One B-rep face of a CAD part: STEP entity #77214.
In plain terms, the planar face has unit normal (0, 0, 1).
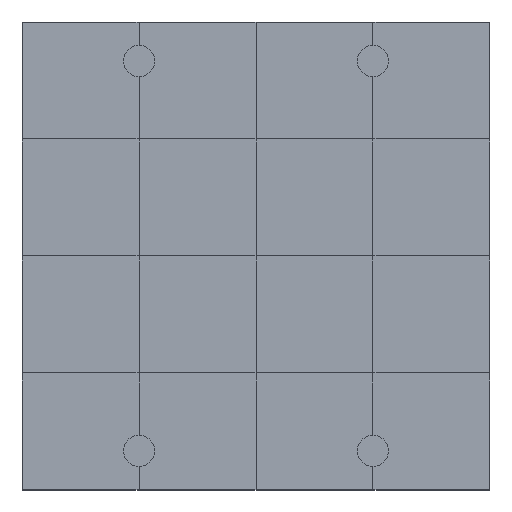
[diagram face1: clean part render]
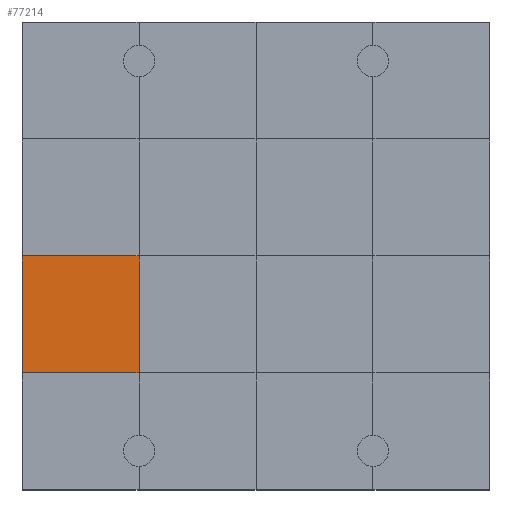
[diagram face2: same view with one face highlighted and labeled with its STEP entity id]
Its self-contained STEP definition (entity closure, numbers rounded to 3 decimals):
#76764 = VERTEX_POINT('',#76765);
#76765 = CARTESIAN_POINT('',(0.,3.,1.2));
#76779 = PLANE('',#76780);
#76780 = AXIS2_PLACEMENT_3D('',#76781,#76782,#76783);
#76781 = CARTESIAN_POINT('',(0.,3.,0.));
#76782 = DIRECTION('',(1.,0.,-0.));
#76783 = DIRECTION('',(0.,0.,1.));
#76805 = PLANE('',#76806);
#76806 = AXIS2_PLACEMENT_3D('',#76807,#76808,#76809);
#76807 = CARTESIAN_POINT('',(0.,0.,1.2));
#76808 = DIRECTION('',(0.,0.,1.));
#76809 = DIRECTION('',(1.,0.,-0.));
#76956 = VERTEX_POINT('',#76957);
#76957 = CARTESIAN_POINT('',(3.,3.,1.2));
#76978 = EDGE_CURVE('',#76764,#76956,#76979,.T.);
#76979 = SURFACE_CURVE('',#76980,(#76984,#76991),.PCURVE_S1.);
#76980 = LINE('',#76981,#76982);
#76981 = CARTESIAN_POINT('',(0.,3.,1.2));
#76982 = VECTOR('',#76983,1.);
#76983 = DIRECTION('',(1.,0.,-0.));
#76984 = PCURVE('',#76805,#76985);
#76985 = DEFINITIONAL_REPRESENTATION('',(#76986),#76990);
#76986 = LINE('',#76987,#76988);
#76987 = CARTESIAN_POINT('',(0.,3.));
#76988 = VECTOR('',#76989,1.);
#76989 = DIRECTION('',(1.,0.));
#76990 = ( GEOMETRIC_REPRESENTATION_CONTEXT(2) 
PARAMETRIC_REPRESENTATION_CONTEXT() REPRESENTATION_CONTEXT('2D SPACE',''
  ) );
#76991 = PCURVE('',#76992,#76997);
#76992 = PLANE('',#76993);
#76993 = AXIS2_PLACEMENT_3D('',#76994,#76995,#76996);
#76994 = CARTESIAN_POINT('',(0.,3.,1.2));
#76995 = DIRECTION('',(0.,0.,1.));
#76996 = DIRECTION('',(1.,0.,-0.));
#76997 = DEFINITIONAL_REPRESENTATION('',(#76998),#77002);
#76998 = LINE('',#76999,#77000);
#76999 = CARTESIAN_POINT('',(0.,0.));
#77000 = VECTOR('',#77001,1.);
#77001 = DIRECTION('',(1.,0.));
#77002 = ( GEOMETRIC_REPRESENTATION_CONTEXT(2) 
PARAMETRIC_REPRESENTATION_CONTEXT() REPRESENTATION_CONTEXT('2D SPACE',''
  ) );
#77037 = VERTEX_POINT('',#77038);
#77038 = CARTESIAN_POINT('',(0.,6.,1.2));
#77064 = EDGE_CURVE('',#76764,#77037,#77065,.T.);
#77065 = SURFACE_CURVE('',#77066,(#77070,#77077),.PCURVE_S1.);
#77066 = LINE('',#77067,#77068);
#77067 = CARTESIAN_POINT('',(0.,3.,1.2));
#77068 = VECTOR('',#77069,1.);
#77069 = DIRECTION('',(-0.,1.,0.));
#77070 = PCURVE('',#76779,#77071);
#77071 = DEFINITIONAL_REPRESENTATION('',(#77072),#77076);
#77072 = LINE('',#77073,#77074);
#77073 = CARTESIAN_POINT('',(1.2,0.));
#77074 = VECTOR('',#77075,1.);
#77075 = DIRECTION('',(0.,-1.));
#77076 = ( GEOMETRIC_REPRESENTATION_CONTEXT(2) 
PARAMETRIC_REPRESENTATION_CONTEXT() REPRESENTATION_CONTEXT('2D SPACE',''
  ) );
#77077 = PCURVE('',#76992,#77078);
#77078 = DEFINITIONAL_REPRESENTATION('',(#77079),#77083);
#77079 = LINE('',#77080,#77081);
#77080 = CARTESIAN_POINT('',(0.,0.));
#77081 = VECTOR('',#77082,1.);
#77082 = DIRECTION('',(0.,1.));
#77083 = ( GEOMETRIC_REPRESENTATION_CONTEXT(2) 
PARAMETRIC_REPRESENTATION_CONTEXT() REPRESENTATION_CONTEXT('2D SPACE',''
  ) );
#77214 = ADVANCED_FACE('',(#77215),#76992,.T.);
#77215 = FACE_BOUND('',#77216,.T.);
#77216 = EDGE_LOOP('',(#77217,#77218,#77219,#77247));
#77217 = ORIENTED_EDGE('',*,*,#77064,.F.);
#77218 = ORIENTED_EDGE('',*,*,#76978,.T.);
#77219 = ORIENTED_EDGE('',*,*,#77220,.T.);
#77220 = EDGE_CURVE('',#76956,#77221,#77223,.T.);
#77221 = VERTEX_POINT('',#77222);
#77222 = CARTESIAN_POINT('',(3.,6.,1.2));
#77223 = SURFACE_CURVE('',#77224,(#77228,#77235),.PCURVE_S1.);
#77224 = LINE('',#77225,#77226);
#77225 = CARTESIAN_POINT('',(3.,3.,1.2));
#77226 = VECTOR('',#77227,1.);
#77227 = DIRECTION('',(-0.,1.,0.));
#77228 = PCURVE('',#76992,#77229);
#77229 = DEFINITIONAL_REPRESENTATION('',(#77230),#77234);
#77230 = LINE('',#77231,#77232);
#77231 = CARTESIAN_POINT('',(3.,0.));
#77232 = VECTOR('',#77233,1.);
#77233 = DIRECTION('',(0.,1.));
#77234 = ( GEOMETRIC_REPRESENTATION_CONTEXT(2) 
PARAMETRIC_REPRESENTATION_CONTEXT() REPRESENTATION_CONTEXT('2D SPACE',''
  ) );
#77235 = PCURVE('',#77236,#77241);
#77236 = PLANE('',#77237);
#77237 = AXIS2_PLACEMENT_3D('',#77238,#77239,#77240);
#77238 = CARTESIAN_POINT('',(3.,3.,1.2));
#77239 = DIRECTION('',(0.,0.,1.));
#77240 = DIRECTION('',(1.,0.,-0.));
#77241 = DEFINITIONAL_REPRESENTATION('',(#77242),#77246);
#77242 = LINE('',#77243,#77244);
#77243 = CARTESIAN_POINT('',(0.,0.));
#77244 = VECTOR('',#77245,1.);
#77245 = DIRECTION('',(0.,1.));
#77246 = ( GEOMETRIC_REPRESENTATION_CONTEXT(2) 
PARAMETRIC_REPRESENTATION_CONTEXT() REPRESENTATION_CONTEXT('2D SPACE',''
  ) );
#77247 = ORIENTED_EDGE('',*,*,#77248,.F.);
#77248 = EDGE_CURVE('',#77037,#77221,#77249,.T.);
#77249 = SURFACE_CURVE('',#77250,(#77254,#77261),.PCURVE_S1.);
#77250 = LINE('',#77251,#77252);
#77251 = CARTESIAN_POINT('',(0.,6.,1.2));
#77252 = VECTOR('',#77253,1.);
#77253 = DIRECTION('',(1.,0.,-0.));
#77254 = PCURVE('',#76992,#77255);
#77255 = DEFINITIONAL_REPRESENTATION('',(#77256),#77260);
#77256 = LINE('',#77257,#77258);
#77257 = CARTESIAN_POINT('',(0.,3.));
#77258 = VECTOR('',#77259,1.);
#77259 = DIRECTION('',(1.,0.));
#77260 = ( GEOMETRIC_REPRESENTATION_CONTEXT(2) 
PARAMETRIC_REPRESENTATION_CONTEXT() REPRESENTATION_CONTEXT('2D SPACE',''
  ) );
#77261 = PCURVE('',#77262,#77267);
#77262 = PLANE('',#77263);
#77263 = AXIS2_PLACEMENT_3D('',#77264,#77265,#77266);
#77264 = CARTESIAN_POINT('',(0.,6.,1.2));
#77265 = DIRECTION('',(0.,0.,1.));
#77266 = DIRECTION('',(1.,0.,-0.));
#77267 = DEFINITIONAL_REPRESENTATION('',(#77268),#77272);
#77268 = LINE('',#77269,#77270);
#77269 = CARTESIAN_POINT('',(0.,0.));
#77270 = VECTOR('',#77271,1.);
#77271 = DIRECTION('',(1.,0.));
#77272 = ( GEOMETRIC_REPRESENTATION_CONTEXT(2) 
PARAMETRIC_REPRESENTATION_CONTEXT() REPRESENTATION_CONTEXT('2D SPACE',''
  ) );
